VERSION 5.7 ;
  NOWIREEXTENSIONATPIN ON ;
  DIVIDERCHAR "/" ;
  BUSBITCHARS "[]" ;
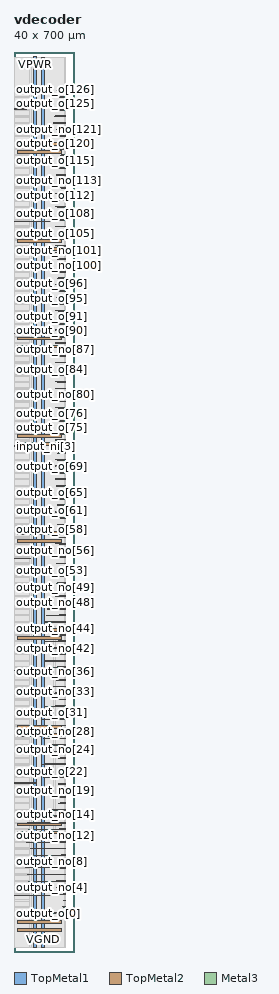
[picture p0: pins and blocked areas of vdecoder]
MACRO vdecoder
  CLASS BLOCK ;
  FOREIGN vdecoder ;
  ORIGIN 0.000 0.000 ;
  SIZE 40.000 BY 700.000 ;
  PIN VGND
    DIRECTION INOUT ;
    USE GROUND ;
    PORT
      LAYER TopMetal1 ;
        RECT 21.580 3.150 23.780 695.740 ;
    END
    PORT
      LAYER TopMetal2 ;
        RECT 2.660 22.480 37.180 24.680 ;
    END
    PORT
      LAYER TopMetal2 ;
        RECT 2.660 98.080 37.180 100.280 ;
    END
    PORT
      LAYER TopMetal2 ;
        RECT 2.660 173.680 37.180 175.880 ;
    END
    PORT
      LAYER TopMetal2 ;
        RECT 2.660 249.280 37.180 251.480 ;
    END
    PORT
      LAYER TopMetal2 ;
        RECT 2.660 324.880 37.180 327.080 ;
    END
    PORT
      LAYER TopMetal2 ;
        RECT 2.660 400.480 37.180 402.680 ;
    END
    PORT
      LAYER TopMetal2 ;
        RECT 2.660 476.080 37.180 478.280 ;
    END
    PORT
      LAYER TopMetal2 ;
        RECT 2.660 551.680 37.180 553.880 ;
    END
    PORT
      LAYER TopMetal2 ;
        RECT 2.660 627.280 37.180 629.480 ;
    END
  END VGND
  PIN VPWR
    DIRECTION INOUT ;
    USE POWER ;
    PORT
      LAYER TopMetal1 ;
        RECT 15.380 3.560 17.580 696.150 ;
    END
    PORT
      LAYER TopMetal2 ;
        RECT 2.660 16.280 37.180 18.480 ;
    END
    PORT
      LAYER TopMetal2 ;
        RECT 2.660 91.880 37.180 94.080 ;
    END
    PORT
      LAYER TopMetal2 ;
        RECT 2.660 167.480 37.180 169.680 ;
    END
    PORT
      LAYER TopMetal2 ;
        RECT 2.660 243.080 37.180 245.280 ;
    END
    PORT
      LAYER TopMetal2 ;
        RECT 2.660 318.680 37.180 320.880 ;
    END
    PORT
      LAYER TopMetal2 ;
        RECT 2.660 394.280 37.180 396.480 ;
    END
    PORT
      LAYER TopMetal2 ;
        RECT 2.660 469.880 37.180 472.080 ;
    END
    PORT
      LAYER TopMetal2 ;
        RECT 2.660 545.480 37.180 547.680 ;
    END
    PORT
      LAYER TopMetal2 ;
        RECT 2.660 621.080 37.180 623.280 ;
    END
  END VPWR
  PIN ena_i
    DIRECTION INPUT ;
    USE SIGNAL ;
    ANTENNAGATEAREA 7.350200 ;
    PORT
      LAYER Metal3 ;
        RECT 0.000 44.000 29.180 44.200 ;
    END
  END ena_i
  PIN input_ni[0]
    DIRECTION INPUT ;
    USE SIGNAL ;
    ANTENNAGATEAREA 1.992900 ;
    PORT
      LAYER Metal3 ;
        RECT 0.000 131.360 17.660 131.560 ;
    END
  END input_ni[0]
  PIN input_ni[1]
    DIRECTION INPUT ;
    USE SIGNAL ;
    ANTENNAGATEAREA 1.992900 ;
    PORT
      LAYER Metal3 ;
        RECT 0.000 218.720 18.620 218.920 ;
    END
  END input_ni[1]
  PIN input_ni[2]
    DIRECTION INPUT ;
    USE SIGNAL ;
    ANTENNAGATEAREA 3.706300 ;
    PORT
      LAYER Metal3 ;
        RECT 0.000 306.080 12.580 306.280 ;
    END
  END input_ni[2]
  PIN input_ni[3]
    DIRECTION INPUT ;
    USE SIGNAL ;
    ANTENNAGATEAREA 3.706300 ;
    PORT
      LAYER Metal3 ;
        RECT 0.000 393.440 1.060 393.640 ;
    END
  END input_ni[3]
  PIN input_ni[4]
    DIRECTION INPUT ;
    USE SIGNAL ;
    ANTENNAGATEAREA 2.008500 ;
    PORT
      LAYER Metal3 ;
        RECT 0.000 480.800 29.660 481.000 ;
    END
  END input_ni[4]
  PIN input_ni[5]
    DIRECTION INPUT ;
    USE SIGNAL ;
    ANTENNAGATEAREA 2.008500 ;
    PORT
      LAYER Metal3 ;
        RECT 0.000 568.160 28.700 568.360 ;
    END
  END input_ni[5]
  PIN input_ni[6]
    DIRECTION INPUT ;
    USE SIGNAL ;
    ANTENNAGATEAREA 2.984800 ;
    PORT
      LAYER Metal3 ;
        RECT 0.000 655.520 9.500 655.720 ;
    END
  END input_ni[6]
  PIN output_no[0]
    DIRECTION OUTPUT ;
    USE SIGNAL ;
    ANTENNADIFFAREA 0.677200 ;
    PORT
      LAYER Metal3 ;
        RECT 30.340 30.140 40.000 30.340 ;
    END
  END output_no[0]
  PIN output_no[100]
    DIRECTION OUTPUT ;
    USE SIGNAL ;
    ANTENNADIFFAREA 0.677200 ;
    PORT
      LAYER Metal3 ;
        RECT 36.100 534.140 40.000 534.340 ;
    END
  END output_no[100]
  PIN output_no[101]
    DIRECTION OUTPUT ;
    USE SIGNAL ;
    ANTENNADIFFAREA 0.677200 ;
    PORT
      LAYER Metal3 ;
        RECT 34.460 539.180 40.000 539.380 ;
    END
  END output_no[101]
  PIN output_no[102]
    DIRECTION OUTPUT ;
    USE SIGNAL ;
    ANTENNADIFFAREA 0.677200 ;
    PORT
      LAYER Metal3 ;
        RECT 32.260 544.220 40.000 544.420 ;
    END
  END output_no[102]
  PIN output_no[103]
    DIRECTION OUTPUT ;
    USE SIGNAL ;
    ANTENNADIFFAREA 0.677200 ;
    PORT
      LAYER Metal3 ;
        RECT 32.260 549.260 40.000 549.460 ;
    END
  END output_no[103]
  PIN output_no[104]
    DIRECTION OUTPUT ;
    USE SIGNAL ;
    ANTENNADIFFAREA 0.677200 ;
    PORT
      LAYER Metal3 ;
        RECT 36.100 554.300 40.000 554.500 ;
    END
  END output_no[104]
  PIN output_no[105]
    DIRECTION OUTPUT ;
    USE SIGNAL ;
    ANTENNADIFFAREA 0.677200 ;
    PORT
      LAYER Metal3 ;
        RECT 34.180 559.340 40.000 559.540 ;
    END
  END output_no[105]
  PIN output_no[106]
    DIRECTION OUTPUT ;
    USE SIGNAL ;
    ANTENNADIFFAREA 0.677200 ;
    PORT
      LAYER Metal3 ;
        RECT 32.260 564.380 40.000 564.580 ;
    END
  END output_no[106]
  PIN output_no[107]
    DIRECTION OUTPUT ;
    USE SIGNAL ;
    ANTENNADIFFAREA 0.677200 ;
    PORT
      LAYER Metal3 ;
        RECT 36.100 569.420 40.000 569.620 ;
    END
  END output_no[107]
  PIN output_no[108]
    DIRECTION OUTPUT ;
    USE SIGNAL ;
    ANTENNADIFFAREA 0.677200 ;
    PORT
      LAYER Metal3 ;
        RECT 34.180 574.460 40.000 574.660 ;
    END
  END output_no[108]
  PIN output_no[109]
    DIRECTION OUTPUT ;
    USE SIGNAL ;
    ANTENNADIFFAREA 0.677200 ;
    PORT
      LAYER Metal3 ;
        RECT 32.260 579.500 40.000 579.700 ;
    END
  END output_no[109]
  PIN output_no[10]
    DIRECTION OUTPUT ;
    USE SIGNAL ;
    ANTENNADIFFAREA 0.677200 ;
    PORT
      LAYER Metal3 ;
        RECT 36.580 80.540 40.000 80.740 ;
    END
  END output_no[10]
  PIN output_no[110]
    DIRECTION OUTPUT ;
    USE SIGNAL ;
    ANTENNADIFFAREA 0.677200 ;
    PORT
      LAYER Metal3 ;
        RECT 36.100 584.540 40.000 584.740 ;
    END
  END output_no[110]
  PIN output_no[111]
    DIRECTION OUTPUT ;
    USE SIGNAL ;
    ANTENNADIFFAREA 0.677200 ;
    PORT
      LAYER Metal3 ;
        RECT 32.260 589.580 40.000 589.780 ;
    END
  END output_no[111]
  PIN output_no[112]
    DIRECTION OUTPUT ;
    USE SIGNAL ;
    ANTENNADIFFAREA 0.677200 ;
    PORT
      LAYER Metal3 ;
        RECT 36.380 594.620 40.000 594.820 ;
    END
  END output_no[112]
  PIN output_no[113]
    DIRECTION OUTPUT ;
    USE SIGNAL ;
    ANTENNADIFFAREA 0.677200 ;
    PORT
      LAYER Metal3 ;
        RECT 38.780 599.660 40.000 599.860 ;
    END
  END output_no[113]
  PIN output_no[114]
    DIRECTION OUTPUT ;
    USE SIGNAL ;
    ANTENNADIFFAREA 0.677200 ;
    PORT
      LAYER Metal3 ;
        RECT 37.060 604.700 40.000 604.900 ;
    END
  END output_no[114]
  PIN output_no[115]
    DIRECTION OUTPUT ;
    USE SIGNAL ;
    ANTENNADIFFAREA 0.677200 ;
    PORT
      LAYER Metal3 ;
        RECT 30.340 609.740 40.000 609.940 ;
    END
  END output_no[115]
  PIN output_no[116]
    DIRECTION OUTPUT ;
    USE SIGNAL ;
    ANTENNADIFFAREA 0.677200 ;
    PORT
      LAYER Metal3 ;
        RECT 37.540 614.780 40.000 614.980 ;
    END
  END output_no[116]
  PIN output_no[117]
    DIRECTION OUTPUT ;
    USE SIGNAL ;
    ANTENNADIFFAREA 0.677200 ;
    PORT
      LAYER Metal3 ;
        RECT 37.060 619.820 40.000 620.020 ;
    END
  END output_no[117]
  PIN output_no[118]
    DIRECTION OUTPUT ;
    USE SIGNAL ;
    ANTENNADIFFAREA 0.677200 ;
    PORT
      LAYER Metal3 ;
        RECT 37.540 624.860 40.000 625.060 ;
    END
  END output_no[118]
  PIN output_no[119]
    DIRECTION OUTPUT ;
    USE SIGNAL ;
    ANTENNADIFFAREA 0.677200 ;
    PORT
      LAYER Metal3 ;
        RECT 35.420 629.900 40.000 630.100 ;
    END
  END output_no[119]
  PIN output_no[11]
    DIRECTION OUTPUT ;
    USE SIGNAL ;
    ANTENNADIFFAREA 0.677200 ;
    PORT
      LAYER Metal3 ;
        RECT 30.820 85.580 40.000 85.780 ;
    END
  END output_no[11]
  PIN output_no[120]
    DIRECTION OUTPUT ;
    USE SIGNAL ;
    ANTENNADIFFAREA 0.677200 ;
    PORT
      LAYER Metal3 ;
        RECT 31.780 634.940 40.000 635.140 ;
    END
  END output_no[120]
  PIN output_no[121]
    DIRECTION OUTPUT ;
    USE SIGNAL ;
    ANTENNADIFFAREA 0.677200 ;
    PORT
      LAYER Metal3 ;
        RECT 38.980 639.980 40.000 640.180 ;
    END
  END output_no[121]
  PIN output_no[122]
    DIRECTION OUTPUT ;
    USE SIGNAL ;
    ANTENNADIFFAREA 0.677200 ;
    PORT
      LAYER Metal3 ;
        RECT 34.180 645.020 40.000 645.220 ;
    END
  END output_no[122]
  PIN output_no[123]
    DIRECTION OUTPUT ;
    USE SIGNAL ;
    ANTENNADIFFAREA 0.677200 ;
    PORT
      LAYER Metal3 ;
        RECT 32.260 650.060 40.000 650.260 ;
    END
  END output_no[123]
  PIN output_no[124]
    DIRECTION OUTPUT ;
    USE SIGNAL ;
    ANTENNADIFFAREA 0.677200 ;
    PORT
      LAYER Metal3 ;
        RECT 30.820 655.100 40.000 655.300 ;
    END
  END output_no[124]
  PIN output_no[125]
    DIRECTION OUTPUT ;
    USE SIGNAL ;
    ANTENNADIFFAREA 0.677200 ;
    PORT
      LAYER Metal3 ;
        RECT 38.500 660.140 40.000 660.340 ;
    END
  END output_no[125]
  PIN output_no[126]
    DIRECTION OUTPUT ;
    USE SIGNAL ;
    ANTENNADIFFAREA 0.677200 ;
    PORT
      LAYER Metal3 ;
        RECT 31.780 665.180 40.000 665.380 ;
    END
  END output_no[126]
  PIN output_no[127]
    DIRECTION OUTPUT ;
    USE SIGNAL ;
    ANTENNADIFFAREA 0.677200 ;
    PORT
      LAYER Metal3 ;
        RECT 33.220 670.220 40.000 670.420 ;
    END
  END output_no[127]
  PIN output_no[12]
    DIRECTION OUTPUT ;
    USE SIGNAL ;
    ANTENNADIFFAREA 0.677200 ;
    PORT
      LAYER Metal3 ;
        RECT 38.780 90.620 40.000 90.820 ;
    END
  END output_no[12]
  PIN output_no[13]
    DIRECTION OUTPUT ;
    USE SIGNAL ;
    ANTENNADIFFAREA 0.677200 ;
    PORT
      LAYER Metal3 ;
        RECT 35.140 95.660 40.000 95.860 ;
    END
  END output_no[13]
  PIN output_no[14]
    DIRECTION OUTPUT ;
    USE SIGNAL ;
    ANTENNADIFFAREA 0.677200 ;
    PORT
      LAYER Metal3 ;
        RECT 37.060 100.700 40.000 100.900 ;
    END
  END output_no[14]
  PIN output_no[15]
    DIRECTION OUTPUT ;
    USE SIGNAL ;
    ANTENNADIFFAREA 0.677200 ;
    PORT
      LAYER Metal3 ;
        RECT 17.660 105.740 40.000 105.940 ;
    END
  END output_no[15]
  PIN output_no[16]
    DIRECTION OUTPUT ;
    USE SIGNAL ;
    ANTENNADIFFAREA 0.677200 ;
    PORT
      LAYER Metal3 ;
        RECT 32.060 110.780 40.000 110.980 ;
    END
  END output_no[16]
  PIN output_no[17]
    DIRECTION OUTPUT ;
    USE SIGNAL ;
    ANTENNADIFFAREA 0.677200 ;
    PORT
      LAYER Metal3 ;
        RECT 36.100 115.820 40.000 116.020 ;
    END
  END output_no[17]
  PIN output_no[18]
    DIRECTION OUTPUT ;
    USE SIGNAL ;
    ANTENNADIFFAREA 0.677200 ;
    PORT
      LAYER Metal3 ;
        RECT 36.100 120.860 40.000 121.060 ;
    END
  END output_no[18]
  PIN output_no[19]
    DIRECTION OUTPUT ;
    USE SIGNAL ;
    ANTENNADIFFAREA 0.677200 ;
    PORT
      LAYER Metal3 ;
        RECT 36.100 125.900 40.000 126.100 ;
    END
  END output_no[19]
  PIN output_no[1]
    DIRECTION OUTPUT ;
    USE SIGNAL ;
    ANTENNADIFFAREA 0.677200 ;
    PORT
      LAYER Metal3 ;
        RECT 38.020 35.180 40.000 35.380 ;
    END
  END output_no[1]
  PIN output_no[20]
    DIRECTION OUTPUT ;
    USE SIGNAL ;
    ANTENNADIFFAREA 0.677200 ;
    PORT
      LAYER Metal3 ;
        RECT 36.100 130.940 40.000 131.140 ;
    END
  END output_no[20]
  PIN output_no[21]
    DIRECTION OUTPUT ;
    USE SIGNAL ;
    ANTENNADIFFAREA 1.058000 ;
    PORT
      LAYER Metal3 ;
        RECT 34.660 135.980 40.000 136.180 ;
    END
  END output_no[21]
  PIN output_no[22]
    DIRECTION OUTPUT ;
    USE SIGNAL ;
    ANTENNADIFFAREA 1.058000 ;
    PORT
      LAYER Metal3 ;
        RECT 34.460 141.020 40.000 141.220 ;
    END
  END output_no[22]
  PIN output_no[23]
    DIRECTION OUTPUT ;
    USE SIGNAL ;
    ANTENNADIFFAREA 1.058000 ;
    PORT
      LAYER Metal3 ;
        RECT 24.860 146.060 40.000 146.260 ;
    END
  END output_no[23]
  PIN output_no[24]
    DIRECTION OUTPUT ;
    USE SIGNAL ;
    ANTENNADIFFAREA 0.677200 ;
    PORT
      LAYER Metal3 ;
        RECT 36.100 151.100 40.000 151.300 ;
    END
  END output_no[24]
  PIN output_no[25]
    DIRECTION OUTPUT ;
    USE SIGNAL ;
    ANTENNADIFFAREA 1.058000 ;
    PORT
      LAYER Metal3 ;
        RECT 33.980 156.140 40.000 156.340 ;
    END
  END output_no[25]
  PIN output_no[26]
    DIRECTION OUTPUT ;
    USE SIGNAL ;
    ANTENNADIFFAREA 1.058000 ;
    PORT
      LAYER Metal3 ;
        RECT 27.740 161.180 40.000 161.380 ;
    END
  END output_no[26]
  PIN output_no[27]
    DIRECTION OUTPUT ;
    USE SIGNAL ;
    ANTENNADIFFAREA 1.058000 ;
    PORT
      LAYER Metal3 ;
        RECT 28.420 166.220 40.000 166.420 ;
    END
  END output_no[27]
  PIN output_no[28]
    DIRECTION OUTPUT ;
    USE SIGNAL ;
    ANTENNADIFFAREA 0.677200 ;
    PORT
      LAYER Metal3 ;
        RECT 36.100 171.260 40.000 171.460 ;
    END
  END output_no[28]
  PIN output_no[29]
    DIRECTION OUTPUT ;
    USE SIGNAL ;
    ANTENNADIFFAREA 1.058000 ;
    PORT
      LAYER Metal3 ;
        RECT 34.660 176.300 40.000 176.500 ;
    END
  END output_no[29]
  PIN output_no[2]
    DIRECTION OUTPUT ;
    USE SIGNAL ;
    ANTENNADIFFAREA 0.677200 ;
    PORT
      LAYER Metal3 ;
        RECT 38.500 40.220 40.000 40.420 ;
    END
  END output_no[2]
  PIN output_no[30]
    DIRECTION OUTPUT ;
    USE SIGNAL ;
    ANTENNADIFFAREA 1.058000 ;
    PORT
      LAYER Metal3 ;
        RECT 34.660 181.340 40.000 181.540 ;
    END
  END output_no[30]
  PIN output_no[31]
    DIRECTION OUTPUT ;
    USE SIGNAL ;
    ANTENNADIFFAREA 0.677200 ;
    PORT
      LAYER Metal3 ;
        RECT 34.180 186.380 40.000 186.580 ;
    END
  END output_no[31]
  PIN output_no[32]
    DIRECTION OUTPUT ;
    USE SIGNAL ;
    ANTENNADIFFAREA 0.677200 ;
    PORT
      LAYER Metal3 ;
        RECT 32.260 191.420 40.000 191.620 ;
    END
  END output_no[32]
  PIN output_no[33]
    DIRECTION OUTPUT ;
    USE SIGNAL ;
    ANTENNADIFFAREA 0.677200 ;
    PORT
      LAYER Metal3 ;
        RECT 35.620 196.460 40.000 196.660 ;
    END
  END output_no[33]
  PIN output_no[34]
    DIRECTION OUTPUT ;
    USE SIGNAL ;
    ANTENNADIFFAREA 0.677200 ;
    PORT
      LAYER Metal3 ;
        RECT 32.260 201.500 40.000 201.700 ;
    END
  END output_no[34]
  PIN output_no[35]
    DIRECTION OUTPUT ;
    USE SIGNAL ;
    ANTENNADIFFAREA 0.677200 ;
    PORT
      LAYER Metal3 ;
        RECT 34.180 206.540 40.000 206.740 ;
    END
  END output_no[35]
  PIN output_no[36]
    DIRECTION OUTPUT ;
    USE SIGNAL ;
    ANTENNADIFFAREA 0.677200 ;
    PORT
      LAYER Metal3 ;
        RECT 34.660 211.580 40.000 211.780 ;
    END
  END output_no[36]
  PIN output_no[37]
    DIRECTION OUTPUT ;
    USE SIGNAL ;
    ANTENNADIFFAREA 1.058000 ;
    PORT
      LAYER Metal3 ;
        RECT 33.980 216.620 40.000 216.820 ;
    END
  END output_no[37]
  PIN output_no[38]
    DIRECTION OUTPUT ;
    USE SIGNAL ;
    ANTENNADIFFAREA 1.058000 ;
    PORT
      LAYER Metal3 ;
        RECT 33.980 221.660 40.000 221.860 ;
    END
  END output_no[38]
  PIN output_no[39]
    DIRECTION OUTPUT ;
    USE SIGNAL ;
    ANTENNADIFFAREA 1.058000 ;
    PORT
      LAYER Metal3 ;
        RECT 29.860 226.700 40.000 226.900 ;
    END
  END output_no[39]
  PIN output_no[3]
    DIRECTION OUTPUT ;
    USE SIGNAL ;
    ANTENNADIFFAREA 0.677200 ;
    PORT
      LAYER Metal3 ;
        RECT 38.780 45.260 40.000 45.460 ;
    END
  END output_no[3]
  PIN output_no[40]
    DIRECTION OUTPUT ;
    USE SIGNAL ;
    ANTENNADIFFAREA 0.677200 ;
    PORT
      LAYER Metal3 ;
        RECT 34.180 231.740 40.000 231.940 ;
    END
  END output_no[40]
  PIN output_no[41]
    DIRECTION OUTPUT ;
    USE SIGNAL ;
    ANTENNADIFFAREA 1.058000 ;
    PORT
      LAYER Metal3 ;
        RECT 33.700 236.780 40.000 236.980 ;
    END
  END output_no[41]
  PIN output_no[42]
    DIRECTION OUTPUT ;
    USE SIGNAL ;
    ANTENNADIFFAREA 1.058000 ;
    PORT
      LAYER Metal3 ;
        RECT 34.660 241.820 40.000 242.020 ;
    END
  END output_no[42]
  PIN output_no[43]
    DIRECTION OUTPUT ;
    USE SIGNAL ;
    ANTENNADIFFAREA 1.058000 ;
    PORT
      LAYER Metal3 ;
        RECT 28.700 246.860 40.000 247.060 ;
    END
  END output_no[43]
  PIN output_no[44]
    DIRECTION OUTPUT ;
    USE SIGNAL ;
    ANTENNADIFFAREA 0.677200 ;
    PORT
      LAYER Metal3 ;
        RECT 37.340 251.900 40.000 252.100 ;
    END
  END output_no[44]
  PIN output_no[45]
    DIRECTION OUTPUT ;
    USE SIGNAL ;
    ANTENNADIFFAREA 1.058000 ;
    PORT
      LAYER Metal3 ;
        RECT 34.180 256.940 40.000 257.140 ;
    END
  END output_no[45]
  PIN output_no[46]
    DIRECTION OUTPUT ;
    USE SIGNAL ;
    ANTENNADIFFAREA 1.058000 ;
    PORT
      LAYER Metal3 ;
        RECT 35.620 261.980 40.000 262.180 ;
    END
  END output_no[46]
  PIN output_no[47]
    DIRECTION OUTPUT ;
    USE SIGNAL ;
    ANTENNADIFFAREA 0.677200 ;
    PORT
      LAYER Metal3 ;
        RECT 32.260 267.020 40.000 267.220 ;
    END
  END output_no[47]
  PIN output_no[48]
    DIRECTION OUTPUT ;
    USE SIGNAL ;
    ANTENNADIFFAREA 0.677200 ;
    PORT
      LAYER Metal3 ;
        RECT 36.100 272.060 40.000 272.260 ;
    END
  END output_no[48]
  PIN output_no[49]
    DIRECTION OUTPUT ;
    USE SIGNAL ;
    ANTENNADIFFAREA 0.677200 ;
    PORT
      LAYER Metal3 ;
        RECT 34.180 277.100 40.000 277.300 ;
    END
  END output_no[49]
  PIN output_no[4]
    DIRECTION OUTPUT ;
    USE SIGNAL ;
    ANTENNADIFFAREA 0.677200 ;
    PORT
      LAYER Metal3 ;
        RECT 38.980 50.300 40.000 50.500 ;
    END
  END output_no[4]
  PIN output_no[50]
    DIRECTION OUTPUT ;
    USE SIGNAL ;
    ANTENNADIFFAREA 0.677200 ;
    PORT
      LAYER Metal3 ;
        RECT 34.180 282.140 40.000 282.340 ;
    END
  END output_no[50]
  PIN output_no[51]
    DIRECTION OUTPUT ;
    USE SIGNAL ;
    ANTENNADIFFAREA 0.677200 ;
    PORT
      LAYER Metal3 ;
        RECT 34.180 287.180 40.000 287.380 ;
    END
  END output_no[51]
  PIN output_no[52]
    DIRECTION OUTPUT ;
    USE SIGNAL ;
    ANTENNADIFFAREA 0.677200 ;
    PORT
      LAYER Metal3 ;
        RECT 34.180 292.220 40.000 292.420 ;
    END
  END output_no[52]
  PIN output_no[53]
    DIRECTION OUTPUT ;
    USE SIGNAL ;
    ANTENNADIFFAREA 0.677200 ;
    PORT
      LAYER Metal3 ;
        RECT 34.180 297.260 40.000 297.460 ;
    END
  END output_no[53]
  PIN output_no[54]
    DIRECTION OUTPUT ;
    USE SIGNAL ;
    ANTENNADIFFAREA 0.677200 ;
    PORT
      LAYER Metal3 ;
        RECT 34.180 302.300 40.000 302.500 ;
    END
  END output_no[54]
  PIN output_no[55]
    DIRECTION OUTPUT ;
    USE SIGNAL ;
    ANTENNADIFFAREA 0.677200 ;
    PORT
      LAYER Metal3 ;
        RECT 34.180 307.340 40.000 307.540 ;
    END
  END output_no[55]
  PIN output_no[56]
    DIRECTION OUTPUT ;
    USE SIGNAL ;
    ANTENNADIFFAREA 0.677200 ;
    PORT
      LAYER Metal3 ;
        RECT 36.380 312.380 40.000 312.580 ;
    END
  END output_no[56]
  PIN output_no[57]
    DIRECTION OUTPUT ;
    USE SIGNAL ;
    ANTENNADIFFAREA 0.677200 ;
    PORT
      LAYER Metal3 ;
        RECT 32.260 317.420 40.000 317.620 ;
    END
  END output_no[57]
  PIN output_no[58]
    DIRECTION OUTPUT ;
    USE SIGNAL ;
    ANTENNADIFFAREA 0.677200 ;
    PORT
      LAYER Metal3 ;
        RECT 34.660 322.460 40.000 322.660 ;
    END
  END output_no[58]
  PIN output_no[59]
    DIRECTION OUTPUT ;
    USE SIGNAL ;
    ANTENNADIFFAREA 0.677200 ;
    PORT
      LAYER Metal3 ;
        RECT 35.620 327.500 40.000 327.700 ;
    END
  END output_no[59]
  PIN output_no[5]
    DIRECTION OUTPUT ;
    USE SIGNAL ;
    ANTENNADIFFAREA 0.677200 ;
    PORT
      LAYER Metal3 ;
        RECT 32.740 55.340 40.000 55.540 ;
    END
  END output_no[5]
  PIN output_no[60]
    DIRECTION OUTPUT ;
    USE SIGNAL ;
    ANTENNADIFFAREA 0.677200 ;
    PORT
      LAYER Metal3 ;
        RECT 34.180 332.540 40.000 332.740 ;
    END
  END output_no[60]
  PIN output_no[61]
    DIRECTION OUTPUT ;
    USE SIGNAL ;
    ANTENNADIFFAREA 0.677200 ;
    PORT
      LAYER Metal3 ;
        RECT 34.180 337.580 40.000 337.780 ;
    END
  END output_no[61]
  PIN output_no[62]
    DIRECTION OUTPUT ;
    USE SIGNAL ;
    ANTENNADIFFAREA 0.677200 ;
    PORT
      LAYER Metal3 ;
        RECT 34.180 342.620 40.000 342.820 ;
    END
  END output_no[62]
  PIN output_no[63]
    DIRECTION OUTPUT ;
    USE SIGNAL ;
    ANTENNADIFFAREA 0.677200 ;
    PORT
      LAYER Metal3 ;
        RECT 34.180 347.660 40.000 347.860 ;
    END
  END output_no[63]
  PIN output_no[64]
    DIRECTION OUTPUT ;
    USE SIGNAL ;
    ANTENNADIFFAREA 0.677200 ;
    PORT
      LAYER Metal3 ;
        RECT 34.180 352.700 40.000 352.900 ;
    END
  END output_no[64]
  PIN output_no[65]
    DIRECTION OUTPUT ;
    USE SIGNAL ;
    ANTENNADIFFAREA 0.677200 ;
    PORT
      LAYER Metal3 ;
        RECT 33.980 357.740 40.000 357.940 ;
    END
  END output_no[65]
  PIN output_no[66]
    DIRECTION OUTPUT ;
    USE SIGNAL ;
    ANTENNADIFFAREA 0.677200 ;
    PORT
      LAYER Metal3 ;
        RECT 34.180 362.780 40.000 362.980 ;
    END
  END output_no[66]
  PIN output_no[67]
    DIRECTION OUTPUT ;
    USE SIGNAL ;
    ANTENNADIFFAREA 0.677200 ;
    PORT
      LAYER Metal3 ;
        RECT 32.260 367.820 40.000 368.020 ;
    END
  END output_no[67]
  PIN output_no[68]
    DIRECTION OUTPUT ;
    USE SIGNAL ;
    ANTENNADIFFAREA 0.677200 ;
    PORT
      LAYER Metal3 ;
        RECT 32.260 372.860 40.000 373.060 ;
    END
  END output_no[68]
  PIN output_no[69]
    DIRECTION OUTPUT ;
    USE SIGNAL ;
    ANTENNADIFFAREA 0.677200 ;
    PORT
      LAYER Metal3 ;
        RECT 32.260 377.900 40.000 378.100 ;
    END
  END output_no[69]
  PIN output_no[6]
    DIRECTION OUTPUT ;
    USE SIGNAL ;
    ANTENNADIFFAREA 0.677200 ;
    PORT
      LAYER Metal3 ;
        RECT 18.820 60.380 40.000 60.580 ;
    END
  END output_no[6]
  PIN output_no[70]
    DIRECTION OUTPUT ;
    USE SIGNAL ;
    ANTENNADIFFAREA 0.677200 ;
    PORT
      LAYER Metal3 ;
        RECT 32.260 382.940 40.000 383.140 ;
    END
  END output_no[70]
  PIN output_no[71]
    DIRECTION OUTPUT ;
    USE SIGNAL ;
    ANTENNADIFFAREA 0.677200 ;
    PORT
      LAYER Metal3 ;
        RECT 34.460 387.980 40.000 388.180 ;
    END
  END output_no[71]
  PIN output_no[72]
    DIRECTION OUTPUT ;
    USE SIGNAL ;
    ANTENNADIFFAREA 0.677200 ;
    PORT
      LAYER Metal3 ;
        RECT 32.260 393.020 40.000 393.220 ;
    END
  END output_no[72]
  PIN output_no[73]
    DIRECTION OUTPUT ;
    USE SIGNAL ;
    ANTENNADIFFAREA 0.677200 ;
    PORT
      LAYER Metal3 ;
        RECT 32.260 398.060 40.000 398.260 ;
    END
  END output_no[73]
  PIN output_no[74]
    DIRECTION OUTPUT ;
    USE SIGNAL ;
    ANTENNADIFFAREA 0.677200 ;
    PORT
      LAYER Metal3 ;
        RECT 32.260 403.100 40.000 403.300 ;
    END
  END output_no[74]
  PIN output_no[75]
    DIRECTION OUTPUT ;
    USE SIGNAL ;
    ANTENNADIFFAREA 0.677200 ;
    PORT
      LAYER Metal3 ;
        RECT 34.180 408.140 40.000 408.340 ;
    END
  END output_no[75]
  PIN output_no[76]
    DIRECTION OUTPUT ;
    USE SIGNAL ;
    ANTENNADIFFAREA 0.677200 ;
    PORT
      LAYER Metal3 ;
        RECT 32.260 413.180 40.000 413.380 ;
    END
  END output_no[76]
  PIN output_no[77]
    DIRECTION OUTPUT ;
    USE SIGNAL ;
    ANTENNADIFFAREA 0.677200 ;
    PORT
      LAYER Metal3 ;
        RECT 34.460 418.220 40.000 418.420 ;
    END
  END output_no[77]
  PIN output_no[78]
    DIRECTION OUTPUT ;
    USE SIGNAL ;
    ANTENNADIFFAREA 0.677200 ;
    PORT
      LAYER Metal3 ;
        RECT 32.260 423.260 40.000 423.460 ;
    END
  END output_no[78]
  PIN output_no[79]
    DIRECTION OUTPUT ;
    USE SIGNAL ;
    ANTENNADIFFAREA 0.677200 ;
    PORT
      LAYER Metal3 ;
        RECT 32.260 428.300 40.000 428.500 ;
    END
  END output_no[79]
  PIN output_no[7]
    DIRECTION OUTPUT ;
    USE SIGNAL ;
    ANTENNADIFFAREA 0.677200 ;
    PORT
      LAYER Metal3 ;
        RECT 8.740 65.420 40.000 65.620 ;
    END
  END output_no[7]
  PIN output_no[80]
    DIRECTION OUTPUT ;
    USE SIGNAL ;
    ANTENNADIFFAREA 0.677200 ;
    PORT
      LAYER Metal3 ;
        RECT 36.100 433.340 40.000 433.540 ;
    END
  END output_no[80]
  PIN output_no[81]
    DIRECTION OUTPUT ;
    USE SIGNAL ;
    ANTENNADIFFAREA 0.677200 ;
    PORT
      LAYER Metal3 ;
        RECT 32.260 438.380 40.000 438.580 ;
    END
  END output_no[81]
  PIN output_no[82]
    DIRECTION OUTPUT ;
    USE SIGNAL ;
    ANTENNADIFFAREA 0.677200 ;
    PORT
      LAYER Metal3 ;
        RECT 32.260 443.420 40.000 443.620 ;
    END
  END output_no[82]
  PIN output_no[83]
    DIRECTION OUTPUT ;
    USE SIGNAL ;
    ANTENNADIFFAREA 0.677200 ;
    PORT
      LAYER Metal3 ;
        RECT 34.460 448.460 40.000 448.660 ;
    END
  END output_no[83]
  PIN output_no[84]
    DIRECTION OUTPUT ;
    USE SIGNAL ;
    ANTENNADIFFAREA 0.677200 ;
    PORT
      LAYER Metal3 ;
        RECT 33.980 453.500 40.000 453.700 ;
    END
  END output_no[84]
  PIN output_no[85]
    DIRECTION OUTPUT ;
    USE SIGNAL ;
    ANTENNADIFFAREA 0.677200 ;
    PORT
      LAYER Metal3 ;
        RECT 32.260 458.540 40.000 458.740 ;
    END
  END output_no[85]
  PIN output_no[86]
    DIRECTION OUTPUT ;
    USE SIGNAL ;
    ANTENNADIFFAREA 0.677200 ;
    PORT
      LAYER Metal3 ;
        RECT 34.460 463.580 40.000 463.780 ;
    END
  END output_no[86]
  PIN output_no[87]
    DIRECTION OUTPUT ;
    USE SIGNAL ;
    ANTENNADIFFAREA 0.677200 ;
    PORT
      LAYER Metal3 ;
        RECT 38.780 468.620 40.000 468.820 ;
    END
  END output_no[87]
  PIN output_no[88]
    DIRECTION OUTPUT ;
    USE SIGNAL ;
    ANTENNADIFFAREA 0.677200 ;
    PORT
      LAYER Metal3 ;
        RECT 32.260 473.660 40.000 473.860 ;
    END
  END output_no[88]
  PIN output_no[89]
    DIRECTION OUTPUT ;
    USE SIGNAL ;
    ANTENNADIFFAREA 0.677200 ;
    PORT
      LAYER Metal3 ;
        RECT 34.460 478.700 40.000 478.900 ;
    END
  END output_no[89]
  PIN output_no[8]
    DIRECTION OUTPUT ;
    USE SIGNAL ;
    ANTENNADIFFAREA 0.677200 ;
    PORT
      LAYER Metal3 ;
        RECT 38.020 70.460 40.000 70.660 ;
    END
  END output_no[8]
  PIN output_no[90]
    DIRECTION OUTPUT ;
    USE SIGNAL ;
    ANTENNADIFFAREA 0.677200 ;
    PORT
      LAYER Metal3 ;
        RECT 32.260 483.740 40.000 483.940 ;
    END
  END output_no[90]
  PIN output_no[91]
    DIRECTION OUTPUT ;
    USE SIGNAL ;
    ANTENNADIFFAREA 0.677200 ;
    PORT
      LAYER Metal3 ;
        RECT 32.260 488.780 40.000 488.980 ;
    END
  END output_no[91]
  PIN output_no[92]
    DIRECTION OUTPUT ;
    USE SIGNAL ;
    ANTENNADIFFAREA 0.677200 ;
    PORT
      LAYER Metal3 ;
        RECT 34.460 493.820 40.000 494.020 ;
    END
  END output_no[92]
  PIN output_no[93]
    DIRECTION OUTPUT ;
    USE SIGNAL ;
    ANTENNADIFFAREA 0.677200 ;
    PORT
      LAYER Metal3 ;
        RECT 32.260 498.860 40.000 499.060 ;
    END
  END output_no[93]
  PIN output_no[94]
    DIRECTION OUTPUT ;
    USE SIGNAL ;
    ANTENNADIFFAREA 0.677200 ;
    PORT
      LAYER Metal3 ;
        RECT 32.260 503.900 40.000 504.100 ;
    END
  END output_no[94]
  PIN output_no[95]
    DIRECTION OUTPUT ;
    USE SIGNAL ;
    ANTENNADIFFAREA 0.677200 ;
    PORT
      LAYER Metal3 ;
        RECT 33.220 508.940 40.000 509.140 ;
    END
  END output_no[95]
  PIN output_no[96]
    DIRECTION OUTPUT ;
    USE SIGNAL ;
    ANTENNADIFFAREA 0.677200 ;
    PORT
      LAYER Metal3 ;
        RECT 34.180 513.980 40.000 514.180 ;
    END
  END output_no[96]
  PIN output_no[97]
    DIRECTION OUTPUT ;
    USE SIGNAL ;
    ANTENNADIFFAREA 0.677200 ;
    PORT
      LAYER Metal3 ;
        RECT 32.260 519.020 40.000 519.220 ;
    END
  END output_no[97]
  PIN output_no[98]
    DIRECTION OUTPUT ;
    USE SIGNAL ;
    ANTENNADIFFAREA 0.677200 ;
    PORT
      LAYER Metal3 ;
        RECT 34.460 524.060 40.000 524.260 ;
    END
  END output_no[98]
  PIN output_no[99]
    DIRECTION OUTPUT ;
    USE SIGNAL ;
    ANTENNADIFFAREA 0.677200 ;
    PORT
      LAYER Metal3 ;
        RECT 32.260 529.100 40.000 529.300 ;
    END
  END output_no[99]
  PIN output_no[9]
    DIRECTION OUTPUT ;
    USE SIGNAL ;
    ANTENNADIFFAREA 0.677200 ;
    PORT
      LAYER Metal3 ;
        RECT 36.860 75.500 40.000 75.700 ;
    END
  END output_no[9]
  PIN output_o[0]
    DIRECTION OUTPUT ;
    USE SIGNAL ;
    ANTENNADIFFAREA 0.662000 ;
    PORT
      LAYER Metal3 ;
        RECT 38.980 29.720 40.000 29.920 ;
    END
  END output_o[0]
  PIN output_o[100]
    DIRECTION OUTPUT ;
    USE SIGNAL ;
    ANTENNADIFFAREA 0.662000 ;
    PORT
      LAYER Metal3 ;
        RECT 34.180 533.720 40.000 533.920 ;
    END
  END output_o[100]
  PIN output_o[101]
    DIRECTION OUTPUT ;
    USE SIGNAL ;
    ANTENNADIFFAREA 0.662000 ;
    PORT
      LAYER Metal3 ;
        RECT 33.980 538.760 40.000 538.960 ;
    END
  END output_o[101]
  PIN output_o[102]
    DIRECTION OUTPUT ;
    USE SIGNAL ;
    ANTENNADIFFAREA 0.662000 ;
    PORT
      LAYER Metal3 ;
        RECT 34.660 543.800 40.000 544.000 ;
    END
  END output_o[102]
  PIN output_o[103]
    DIRECTION OUTPUT ;
    USE SIGNAL ;
    ANTENNADIFFAREA 0.662000 ;
    PORT
      LAYER Metal3 ;
        RECT 34.180 548.840 40.000 549.040 ;
    END
  END output_o[103]
  PIN output_o[104]
    DIRECTION OUTPUT ;
    USE SIGNAL ;
    ANTENNADIFFAREA 0.662000 ;
    PORT
      LAYER Metal3 ;
        RECT 32.060 553.880 40.000 554.080 ;
    END
  END output_o[104]
  PIN output_o[105]
    DIRECTION OUTPUT ;
    USE SIGNAL ;
    ANTENNADIFFAREA 0.662000 ;
    PORT
      LAYER Metal3 ;
        RECT 36.580 558.920 40.000 559.120 ;
    END
  END output_o[105]
  PIN output_o[106]
    DIRECTION OUTPUT ;
    USE SIGNAL ;
    ANTENNADIFFAREA 0.662000 ;
    PORT
      LAYER Metal3 ;
        RECT 34.180 563.960 40.000 564.160 ;
    END
  END output_o[106]
  PIN output_o[107]
    DIRECTION OUTPUT ;
    USE SIGNAL ;
    ANTENNADIFFAREA 0.662000 ;
    PORT
      LAYER Metal3 ;
        RECT 32.060 569.000 40.000 569.200 ;
    END
  END output_o[107]
  PIN output_o[108]
    DIRECTION OUTPUT ;
    USE SIGNAL ;
    ANTENNADIFFAREA 0.662000 ;
    PORT
      LAYER Metal3 ;
        RECT 36.580 574.040 40.000 574.240 ;
    END
  END output_o[108]
  PIN output_o[109]
    DIRECTION OUTPUT ;
    USE SIGNAL ;
    ANTENNADIFFAREA 0.662000 ;
    PORT
      LAYER Metal3 ;
        RECT 34.180 579.080 40.000 579.280 ;
    END
  END output_o[109]
  PIN output_o[10]
    DIRECTION OUTPUT ;
    USE SIGNAL ;
    ANTENNADIFFAREA 0.662000 ;
    PORT
      LAYER Metal3 ;
        RECT 12.580 80.120 40.000 80.320 ;
    END
  END output_o[10]
  PIN output_o[110]
    DIRECTION OUTPUT ;
    USE SIGNAL ;
    ANTENNADIFFAREA 0.662000 ;
    PORT
      LAYER Metal3 ;
        RECT 33.220 584.120 40.000 584.320 ;
    END
  END output_o[110]
  PIN output_o[111]
    DIRECTION OUTPUT ;
    USE SIGNAL ;
    ANTENNADIFFAREA 0.662000 ;
    PORT
      LAYER Metal3 ;
        RECT 34.660 589.160 40.000 589.360 ;
    END
  END output_o[111]
  PIN output_o[112]
    DIRECTION OUTPUT ;
    USE SIGNAL ;
    ANTENNADIFFAREA 0.662000 ;
    PORT
      LAYER Metal3 ;
        RECT 36.860 594.200 40.000 594.400 ;
    END
  END output_o[112]
  PIN output_o[113]
    DIRECTION OUTPUT ;
    USE SIGNAL ;
    ANTENNADIFFAREA 0.662000 ;
    PORT
      LAYER Metal3 ;
        RECT 33.980 599.240 40.000 599.440 ;
    END
  END output_o[113]
  PIN output_o[114]
    DIRECTION OUTPUT ;
    USE SIGNAL ;
    ANTENNADIFFAREA 0.662000 ;
    PORT
      LAYER Metal3 ;
        RECT 32.740 604.280 40.000 604.480 ;
    END
  END output_o[114]
  PIN output_o[115]
    DIRECTION OUTPUT ;
    USE SIGNAL ;
    ANTENNADIFFAREA 0.662000 ;
    PORT
      LAYER Metal3 ;
        RECT 38.020 609.320 40.000 609.520 ;
    END
  END output_o[115]
  PIN output_o[116]
    DIRECTION OUTPUT ;
    USE SIGNAL ;
    ANTENNADIFFAREA 0.662000 ;
    PORT
      LAYER Metal3 ;
        RECT 34.660 614.360 40.000 614.560 ;
    END
  END output_o[116]
  PIN output_o[117]
    DIRECTION OUTPUT ;
    USE SIGNAL ;
    ANTENNADIFFAREA 0.662000 ;
    PORT
      LAYER Metal3 ;
        RECT 36.100 619.400 40.000 619.600 ;
    END
  END output_o[117]
  PIN output_o[118]
    DIRECTION OUTPUT ;
    USE SIGNAL ;
    ANTENNADIFFAREA 0.662000 ;
    PORT
      LAYER Metal3 ;
        RECT 29.860 624.440 40.000 624.640 ;
    END
  END output_o[118]
  PIN output_o[119]
    DIRECTION OUTPUT ;
    USE SIGNAL ;
    ANTENNADIFFAREA 0.662000 ;
    PORT
      LAYER Metal3 ;
        RECT 36.100 629.480 40.000 629.680 ;
    END
  END output_o[119]
  PIN output_o[11]
    DIRECTION OUTPUT ;
    USE SIGNAL ;
    ANTENNADIFFAREA 0.662000 ;
    PORT
      LAYER Metal3 ;
        RECT 9.700 85.160 40.000 85.360 ;
    END
  END output_o[11]
  PIN output_o[120]
    DIRECTION OUTPUT ;
    USE SIGNAL ;
    ANTENNADIFFAREA 0.662000 ;
    PORT
      LAYER Metal3 ;
        RECT 34.660 634.520 40.000 634.720 ;
    END
  END output_o[120]
  PIN output_o[121]
    DIRECTION OUTPUT ;
    USE SIGNAL ;
    ANTENNADIFFAREA 0.662000 ;
    PORT
      LAYER Metal3 ;
        RECT 32.740 639.560 40.000 639.760 ;
    END
  END output_o[121]
  PIN output_o[122]
    DIRECTION OUTPUT ;
    USE SIGNAL ;
    ANTENNADIFFAREA 0.662000 ;
    PORT
      LAYER Metal3 ;
        RECT 30.340 644.600 40.000 644.800 ;
    END
  END output_o[122]
  PIN output_o[123]
    DIRECTION OUTPUT ;
    USE SIGNAL ;
    ANTENNADIFFAREA 0.662000 ;
    PORT
      LAYER Metal3 ;
        RECT 31.300 649.640 40.000 649.840 ;
    END
  END output_o[123]
  PIN output_o[124]
    DIRECTION OUTPUT ;
    USE SIGNAL ;
    ANTENNADIFFAREA 0.662000 ;
    PORT
      LAYER Metal3 ;
        RECT 33.700 654.680 40.000 654.880 ;
    END
  END output_o[124]
  PIN output_o[125]
    DIRECTION OUTPUT ;
    USE SIGNAL ;
    ANTENNADIFFAREA 0.662000 ;
    PORT
      LAYER Metal3 ;
        RECT 38.980 659.720 40.000 659.920 ;
    END
  END output_o[125]
  PIN output_o[126]
    DIRECTION OUTPUT ;
    USE SIGNAL ;
    ANTENNADIFFAREA 0.662000 ;
    PORT
      LAYER Metal3 ;
        RECT 35.140 664.760 40.000 664.960 ;
    END
  END output_o[126]
  PIN output_o[127]
    DIRECTION OUTPUT ;
    USE SIGNAL ;
    ANTENNADIFFAREA 0.662000 ;
    PORT
      LAYER Metal3 ;
        RECT 32.740 669.800 40.000 670.000 ;
    END
  END output_o[127]
  PIN output_o[12]
    DIRECTION OUTPUT ;
    USE SIGNAL ;
    ANTENNADIFFAREA 0.662000 ;
    PORT
      LAYER Metal3 ;
        RECT 34.180 90.200 40.000 90.400 ;
    END
  END output_o[12]
  PIN output_o[13]
    DIRECTION OUTPUT ;
    USE SIGNAL ;
    ANTENNADIFFAREA 0.662000 ;
    PORT
      LAYER Metal3 ;
        RECT 11.140 95.240 40.000 95.440 ;
    END
  END output_o[13]
  PIN output_o[14]
    DIRECTION OUTPUT ;
    USE SIGNAL ;
    ANTENNADIFFAREA 0.662000 ;
    PORT
      LAYER Metal3 ;
        RECT 10.660 100.280 40.000 100.480 ;
    END
  END output_o[14]
  PIN output_o[15]
    DIRECTION OUTPUT ;
    USE SIGNAL ;
    ANTENNADIFFAREA 0.662000 ;
    PORT
      LAYER Metal3 ;
        RECT 12.100 105.320 40.000 105.520 ;
    END
  END output_o[15]
  PIN output_o[16]
    DIRECTION OUTPUT ;
    USE SIGNAL ;
    ANTENNADIFFAREA 0.662000 ;
    PORT
      LAYER Metal3 ;
        RECT 27.460 110.360 40.000 110.560 ;
    END
  END output_o[16]
  PIN output_o[17]
    DIRECTION OUTPUT ;
    USE SIGNAL ;
    ANTENNADIFFAREA 0.632400 ;
    PORT
      LAYER Metal3 ;
        RECT 34.660 115.400 40.000 115.600 ;
    END
  END output_o[17]
  PIN output_o[18]
    DIRECTION OUTPUT ;
    USE SIGNAL ;
    ANTENNADIFFAREA 0.632400 ;
    PORT
      LAYER Metal3 ;
        RECT 34.660 120.440 40.000 120.640 ;
    END
  END output_o[18]
  PIN output_o[19]
    DIRECTION OUTPUT ;
    USE SIGNAL ;
    ANTENNADIFFAREA 0.632400 ;
    PORT
      LAYER Metal3 ;
        RECT 34.660 125.480 40.000 125.680 ;
    END
  END output_o[19]
  PIN output_o[1]
    DIRECTION OUTPUT ;
    USE SIGNAL ;
    ANTENNADIFFAREA 0.662000 ;
    PORT
      LAYER Metal3 ;
        RECT 38.780 34.760 40.000 34.960 ;
    END
  END output_o[1]
  PIN output_o[20]
    DIRECTION OUTPUT ;
    USE SIGNAL ;
    ANTENNADIFFAREA 0.632400 ;
    PORT
      LAYER Metal3 ;
        RECT 34.460 130.520 40.000 130.720 ;
    END
  END output_o[20]
  PIN output_o[21]
    DIRECTION OUTPUT ;
    USE SIGNAL ;
    ANTENNADIFFAREA 0.981400 ;
    PORT
      LAYER Metal3 ;
        RECT 22.660 135.560 40.000 135.760 ;
    END
  END output_o[21]
  PIN output_o[22]
    DIRECTION OUTPUT ;
    USE SIGNAL ;
    ANTENNADIFFAREA 0.981400 ;
    PORT
      LAYER Metal3 ;
        RECT 38.780 140.600 40.000 140.800 ;
    END
  END output_o[22]
  PIN output_o[23]
    DIRECTION OUTPUT ;
    USE SIGNAL ;
    ANTENNADIFFAREA 0.981400 ;
    PORT
      LAYER Metal3 ;
        RECT 21.700 145.640 40.000 145.840 ;
    END
  END output_o[23]
  PIN output_o[24]
    DIRECTION OUTPUT ;
    USE SIGNAL ;
    ANTENNADIFFAREA 0.632400 ;
    PORT
      LAYER Metal3 ;
        RECT 34.660 150.680 40.000 150.880 ;
    END
  END output_o[24]
  PIN output_o[25]
    DIRECTION OUTPUT ;
    USE SIGNAL ;
    ANTENNADIFFAREA 0.981400 ;
    PORT
      LAYER Metal3 ;
        RECT 21.700 155.720 40.000 155.920 ;
    END
  END output_o[25]
  PIN output_o[26]
    DIRECTION OUTPUT ;
    USE SIGNAL ;
    ANTENNADIFFAREA 0.981400 ;
    PORT
      LAYER Metal3 ;
        RECT 21.700 160.760 40.000 160.960 ;
    END
  END output_o[26]
  PIN output_o[27]
    DIRECTION OUTPUT ;
    USE SIGNAL ;
    ANTENNADIFFAREA 0.981400 ;
    PORT
      LAYER Metal3 ;
        RECT 22.660 165.800 40.000 166.000 ;
    END
  END output_o[27]
  PIN output_o[28]
    DIRECTION OUTPUT ;
    USE SIGNAL ;
    ANTENNADIFFAREA 0.632400 ;
    PORT
      LAYER Metal3 ;
        RECT 34.660 170.840 40.000 171.040 ;
    END
  END output_o[28]
  PIN output_o[29]
    DIRECTION OUTPUT ;
    USE SIGNAL ;
    ANTENNADIFFAREA 0.999200 ;
    PORT
      LAYER Metal3 ;
        RECT 21.220 175.880 40.000 176.080 ;
    END
  END output_o[29]
  PIN output_o[2]
    DIRECTION OUTPUT ;
    USE SIGNAL ;
    ANTENNADIFFAREA 0.662000 ;
    PORT
      LAYER Metal3 ;
        RECT 38.500 39.800 40.000 40.000 ;
    END
  END output_o[2]
  PIN output_o[30]
    DIRECTION OUTPUT ;
    USE SIGNAL ;
    ANTENNADIFFAREA 0.999200 ;
    PORT
      LAYER Metal3 ;
        RECT 21.700 180.920 40.000 181.120 ;
    END
  END output_o[30]
  PIN output_o[31]
    DIRECTION OUTPUT ;
    USE SIGNAL ;
    ANTENNADIFFAREA 0.662000 ;
    PORT
      LAYER Metal3 ;
        RECT 35.900 185.960 40.000 186.160 ;
    END
  END output_o[31]
  PIN output_o[32]
    DIRECTION OUTPUT ;
    USE SIGNAL ;
    ANTENNADIFFAREA 0.662000 ;
    PORT
      LAYER Metal3 ;
        RECT 24.380 191.000 40.000 191.200 ;
    END
  END output_o[32]
  PIN output_o[33]
    DIRECTION OUTPUT ;
    USE SIGNAL ;
    ANTENNADIFFAREA 0.632400 ;
    PORT
      LAYER Metal3 ;
        RECT 34.180 196.040 40.000 196.240 ;
    END
  END output_o[33]
  PIN output_o[34]
    DIRECTION OUTPUT ;
    USE SIGNAL ;
    ANTENNADIFFAREA 0.632400 ;
    PORT
      LAYER Metal3 ;
        RECT 28.900 201.080 40.000 201.280 ;
    END
  END output_o[34]
  PIN output_o[35]
    DIRECTION OUTPUT ;
    USE SIGNAL ;
    ANTENNADIFFAREA 0.632400 ;
    PORT
      LAYER Metal3 ;
        RECT 30.620 206.120 40.000 206.320 ;
    END
  END output_o[35]
  PIN output_o[36]
    DIRECTION OUTPUT ;
    USE SIGNAL ;
    ANTENNADIFFAREA 0.632400 ;
    PORT
      LAYER Metal3 ;
        RECT 33.220 211.160 40.000 211.360 ;
    END
  END output_o[36]
  PIN output_o[37]
    DIRECTION OUTPUT ;
    USE SIGNAL ;
    ANTENNADIFFAREA 0.981400 ;
    PORT
      LAYER Metal3 ;
        RECT 34.460 216.200 40.000 216.400 ;
    END
  END output_o[37]
  PIN output_o[38]
    DIRECTION OUTPUT ;
    USE SIGNAL ;
    ANTENNADIFFAREA 0.981400 ;
    PORT
      LAYER Metal3 ;
        RECT 23.140 221.240 40.000 221.440 ;
    END
  END output_o[38]
  PIN output_o[39]
    DIRECTION OUTPUT ;
    USE SIGNAL ;
    ANTENNADIFFAREA 0.981400 ;
    PORT
      LAYER Metal3 ;
        RECT 23.620 226.280 40.000 226.480 ;
    END
  END output_o[39]
  PIN output_o[3]
    DIRECTION OUTPUT ;
    USE SIGNAL ;
    ANTENNADIFFAREA 0.662000 ;
    PORT
      LAYER Metal3 ;
        RECT 34.660 44.840 40.000 45.040 ;
    END
  END output_o[3]
  PIN output_o[40]
    DIRECTION OUTPUT ;
    USE SIGNAL ;
    ANTENNADIFFAREA 0.632400 ;
    PORT
      LAYER Metal3 ;
        RECT 34.660 231.320 40.000 231.520 ;
    END
  END output_o[40]
  PIN output_o[41]
    DIRECTION OUTPUT ;
    USE SIGNAL ;
    ANTENNADIFFAREA 0.981400 ;
    PORT
      LAYER Metal3 ;
        RECT 24.100 236.360 40.000 236.560 ;
    END
  END output_o[41]
  PIN output_o[42]
    DIRECTION OUTPUT ;
    USE SIGNAL ;
    ANTENNADIFFAREA 0.981400 ;
    PORT
      LAYER Metal3 ;
        RECT 24.580 241.400 40.000 241.600 ;
    END
  END output_o[42]
  PIN output_o[43]
    DIRECTION OUTPUT ;
    USE SIGNAL ;
    ANTENNADIFFAREA 0.981400 ;
    PORT
      LAYER Metal3 ;
        RECT 29.180 246.440 40.000 246.640 ;
    END
  END output_o[43]
  PIN output_o[44]
    DIRECTION OUTPUT ;
    USE SIGNAL ;
    ANTENNADIFFAREA 0.632400 ;
    PORT
      LAYER Metal3 ;
        RECT 34.660 251.480 40.000 251.680 ;
    END
  END output_o[44]
  PIN output_o[45]
    DIRECTION OUTPUT ;
    USE SIGNAL ;
    ANTENNADIFFAREA 0.999200 ;
    PORT
      LAYER Metal3 ;
        RECT 24.580 256.520 40.000 256.720 ;
    END
  END output_o[45]
  PIN output_o[46]
    DIRECTION OUTPUT ;
    USE SIGNAL ;
    ANTENNADIFFAREA 0.999200 ;
    PORT
      LAYER Metal3 ;
        RECT 25.540 261.560 40.000 261.760 ;
    END
  END output_o[46]
  PIN output_o[47]
    DIRECTION OUTPUT ;
    USE SIGNAL ;
    ANTENNADIFFAREA 0.662000 ;
    PORT
      LAYER Metal3 ;
        RECT 26.020 266.600 40.000 266.800 ;
    END
  END output_o[47]
  PIN output_o[48]
    DIRECTION OUTPUT ;
    USE SIGNAL ;
    ANTENNADIFFAREA 0.662000 ;
    PORT
      LAYER Metal3 ;
        RECT 33.700 271.640 40.000 271.840 ;
    END
  END output_o[48]
  PIN output_o[49]
    DIRECTION OUTPUT ;
    USE SIGNAL ;
    ANTENNADIFFAREA 0.662000 ;
    PORT
      LAYER Metal3 ;
        RECT 32.260 276.680 40.000 276.880 ;
    END
  END output_o[49]
  PIN output_o[4]
    DIRECTION OUTPUT ;
    USE SIGNAL ;
    ANTENNADIFFAREA 0.662000 ;
    PORT
      LAYER Metal3 ;
        RECT 33.220 49.880 40.000 50.080 ;
    END
  END output_o[4]
  PIN output_o[50]
    DIRECTION OUTPUT ;
    USE SIGNAL ;
    ANTENNADIFFAREA 0.662000 ;
    PORT
      LAYER Metal3 ;
        RECT 35.900 281.720 40.000 281.920 ;
    END
  END output_o[50]
  PIN output_o[51]
    DIRECTION OUTPUT ;
    USE SIGNAL ;
    ANTENNADIFFAREA 0.662000 ;
    PORT
      LAYER Metal3 ;
        RECT 32.740 286.760 40.000 286.960 ;
    END
  END output_o[51]
  PIN output_o[52]
    DIRECTION OUTPUT ;
    USE SIGNAL ;
    ANTENNADIFFAREA 0.662000 ;
    PORT
      LAYER Metal3 ;
        RECT 32.260 291.800 40.000 292.000 ;
    END
  END output_o[52]
  PIN output_o[53]
    DIRECTION OUTPUT ;
    USE SIGNAL ;
    ANTENNADIFFAREA 0.662000 ;
    PORT
      LAYER Metal3 ;
        RECT 36.100 296.840 40.000 297.040 ;
    END
  END output_o[53]
  PIN output_o[54]
    DIRECTION OUTPUT ;
    USE SIGNAL ;
    ANTENNADIFFAREA 0.662000 ;
    PORT
      LAYER Metal3 ;
        RECT 32.740 301.880 40.000 302.080 ;
    END
  END output_o[54]
  PIN output_o[55]
    DIRECTION OUTPUT ;
    USE SIGNAL ;
    ANTENNADIFFAREA 0.662000 ;
    PORT
      LAYER Metal3 ;
        RECT 32.260 306.920 40.000 307.120 ;
    END
  END output_o[55]
  PIN output_o[56]
    DIRECTION OUTPUT ;
    USE SIGNAL ;
    ANTENNADIFFAREA 0.662000 ;
    PORT
      LAYER Metal3 ;
        RECT 35.900 311.960 40.000 312.160 ;
    END
  END output_o[56]
  PIN output_o[57]
    DIRECTION OUTPUT ;
    USE SIGNAL ;
    ANTENNADIFFAREA 0.662000 ;
    PORT
      LAYER Metal3 ;
        RECT 35.140 317.000 40.000 317.200 ;
    END
  END output_o[57]
  PIN output_o[58]
    DIRECTION OUTPUT ;
    USE SIGNAL ;
    ANTENNADIFFAREA 0.662000 ;
    PORT
      LAYER Metal3 ;
        RECT 36.100 322.040 40.000 322.240 ;
    END
  END output_o[58]
  PIN output_o[59]
    DIRECTION OUTPUT ;
    USE SIGNAL ;
    ANTENNADIFFAREA 0.662000 ;
    PORT
      LAYER Metal3 ;
        RECT 34.940 327.080 40.000 327.280 ;
    END
  END output_o[59]
  PIN output_o[5]
    DIRECTION OUTPUT ;
    USE SIGNAL ;
    ANTENNADIFFAREA 0.662000 ;
    PORT
      LAYER Metal3 ;
        RECT 11.620 54.920 40.000 55.120 ;
    END
  END output_o[5]
  PIN output_o[60]
    DIRECTION OUTPUT ;
    USE SIGNAL ;
    ANTENNADIFFAREA 0.662000 ;
    PORT
      LAYER Metal3 ;
        RECT 34.660 332.120 40.000 332.320 ;
    END
  END output_o[60]
  PIN output_o[61]
    DIRECTION OUTPUT ;
    USE SIGNAL ;
    ANTENNADIFFAREA 0.662000 ;
    PORT
      LAYER Metal3 ;
        RECT 36.100 337.160 40.000 337.360 ;
    END
  END output_o[61]
  PIN output_o[62]
    DIRECTION OUTPUT ;
    USE SIGNAL ;
    ANTENNADIFFAREA 0.662000 ;
    PORT
      LAYER Metal3 ;
        RECT 32.060 342.200 40.000 342.400 ;
    END
  END output_o[62]
  PIN output_o[63]
    DIRECTION OUTPUT ;
    USE SIGNAL ;
    ANTENNADIFFAREA 0.662000 ;
    PORT
      LAYER Metal3 ;
        RECT 36.100 347.240 40.000 347.440 ;
    END
  END output_o[63]
  PIN output_o[64]
    DIRECTION OUTPUT ;
    USE SIGNAL ;
    ANTENNADIFFAREA 0.662000 ;
    PORT
      LAYER Metal3 ;
        RECT 32.260 352.280 40.000 352.480 ;
    END
  END output_o[64]
  PIN output_o[65]
    DIRECTION OUTPUT ;
    USE SIGNAL ;
    ANTENNADIFFAREA 0.662000 ;
    PORT
      LAYER Metal3 ;
        RECT 35.620 357.320 40.000 357.520 ;
    END
  END output_o[65]
  PIN output_o[66]
    DIRECTION OUTPUT ;
    USE SIGNAL ;
    ANTENNADIFFAREA 0.662000 ;
    PORT
      LAYER Metal3 ;
        RECT 32.740 362.360 40.000 362.560 ;
    END
  END output_o[66]
  PIN output_o[67]
    DIRECTION OUTPUT ;
    USE SIGNAL ;
    ANTENNADIFFAREA 0.662000 ;
    PORT
      LAYER Metal3 ;
        RECT 34.180 367.400 40.000 367.600 ;
    END
  END output_o[67]
  PIN output_o[68]
    DIRECTION OUTPUT ;
    USE SIGNAL ;
    ANTENNADIFFAREA 0.662000 ;
    PORT
      LAYER Metal3 ;
        RECT 33.980 372.440 40.000 372.640 ;
    END
  END output_o[68]
  PIN output_o[69]
    DIRECTION OUTPUT ;
    USE SIGNAL ;
    ANTENNADIFFAREA 0.662000 ;
    PORT
      LAYER Metal3 ;
        RECT 34.660 377.480 40.000 377.680 ;
    END
  END output_o[69]
  PIN output_o[6]
    DIRECTION OUTPUT ;
    USE SIGNAL ;
    ANTENNADIFFAREA 0.662000 ;
    PORT
      LAYER Metal3 ;
        RECT 10.180 59.960 40.000 60.160 ;
    END
  END output_o[6]
  PIN output_o[70]
    DIRECTION OUTPUT ;
    USE SIGNAL ;
    ANTENNADIFFAREA 0.662000 ;
    PORT
      LAYER Metal3 ;
        RECT 34.180 382.520 40.000 382.720 ;
    END
  END output_o[70]
  PIN output_o[71]
    DIRECTION OUTPUT ;
    USE SIGNAL ;
    ANTENNADIFFAREA 0.662000 ;
    PORT
      LAYER Metal3 ;
        RECT 33.980 387.560 40.000 387.760 ;
    END
  END output_o[71]
  PIN output_o[72]
    DIRECTION OUTPUT ;
    USE SIGNAL ;
    ANTENNADIFFAREA 0.662000 ;
    PORT
      LAYER Metal3 ;
        RECT 34.660 392.600 40.000 392.800 ;
    END
  END output_o[72]
  PIN output_o[73]
    DIRECTION OUTPUT ;
    USE SIGNAL ;
    ANTENNADIFFAREA 0.662000 ;
    PORT
      LAYER Metal3 ;
        RECT 34.180 397.640 40.000 397.840 ;
    END
  END output_o[73]
  PIN output_o[74]
    DIRECTION OUTPUT ;
    USE SIGNAL ;
    ANTENNADIFFAREA 0.662000 ;
    PORT
      LAYER Metal3 ;
        RECT 33.980 402.680 40.000 402.880 ;
    END
  END output_o[74]
  PIN output_o[75]
    DIRECTION OUTPUT ;
    USE SIGNAL ;
    ANTENNADIFFAREA 0.662000 ;
    PORT
      LAYER Metal3 ;
        RECT 34.660 407.720 40.000 407.920 ;
    END
  END output_o[75]
  PIN output_o[76]
    DIRECTION OUTPUT ;
    USE SIGNAL ;
    ANTENNADIFFAREA 0.662000 ;
    PORT
      LAYER Metal3 ;
        RECT 34.180 412.760 40.000 412.960 ;
    END
  END output_o[76]
  PIN output_o[77]
    DIRECTION OUTPUT ;
    USE SIGNAL ;
    ANTENNADIFFAREA 0.662000 ;
    PORT
      LAYER Metal3 ;
        RECT 33.980 417.800 40.000 418.000 ;
    END
  END output_o[77]
  PIN output_o[78]
    DIRECTION OUTPUT ;
    USE SIGNAL ;
    ANTENNADIFFAREA 0.662000 ;
    PORT
      LAYER Metal3 ;
        RECT 34.660 422.840 40.000 423.040 ;
    END
  END output_o[78]
  PIN output_o[79]
    DIRECTION OUTPUT ;
    USE SIGNAL ;
    ANTENNADIFFAREA 0.662000 ;
    PORT
      LAYER Metal3 ;
        RECT 34.180 427.880 40.000 428.080 ;
    END
  END output_o[79]
  PIN output_o[7]
    DIRECTION OUTPUT ;
    USE SIGNAL ;
    ANTENNADIFFAREA 0.662000 ;
    PORT
      LAYER Metal3 ;
        RECT 31.300 65.000 40.000 65.200 ;
    END
  END output_o[7]
  PIN output_o[80]
    DIRECTION OUTPUT ;
    USE SIGNAL ;
    ANTENNADIFFAREA 0.662000 ;
    PORT
      LAYER Metal3 ;
        RECT 33.980 432.920 40.000 433.120 ;
    END
  END output_o[80]
  PIN output_o[81]
    DIRECTION OUTPUT ;
    USE SIGNAL ;
    ANTENNADIFFAREA 0.662000 ;
    PORT
      LAYER Metal3 ;
        RECT 34.660 437.960 40.000 438.160 ;
    END
  END output_o[81]
  PIN output_o[82]
    DIRECTION OUTPUT ;
    USE SIGNAL ;
    ANTENNADIFFAREA 0.662000 ;
    PORT
      LAYER Metal3 ;
        RECT 34.180 443.000 40.000 443.200 ;
    END
  END output_o[82]
  PIN output_o[83]
    DIRECTION OUTPUT ;
    USE SIGNAL ;
    ANTENNADIFFAREA 0.662000 ;
    PORT
      LAYER Metal3 ;
        RECT 33.980 448.040 40.000 448.240 ;
    END
  END output_o[83]
  PIN output_o[84]
    DIRECTION OUTPUT ;
    USE SIGNAL ;
    ANTENNADIFFAREA 0.662000 ;
    PORT
      LAYER Metal3 ;
        RECT 34.660 453.080 40.000 453.280 ;
    END
  END output_o[84]
  PIN output_o[85]
    DIRECTION OUTPUT ;
    USE SIGNAL ;
    ANTENNADIFFAREA 0.662000 ;
    PORT
      LAYER Metal3 ;
        RECT 34.180 458.120 40.000 458.320 ;
    END
  END output_o[85]
  PIN output_o[86]
    DIRECTION OUTPUT ;
    USE SIGNAL ;
    ANTENNADIFFAREA 0.662000 ;
    PORT
      LAYER Metal3 ;
        RECT 33.980 463.160 40.000 463.360 ;
    END
  END output_o[86]
  PIN output_o[87]
    DIRECTION OUTPUT ;
    USE SIGNAL ;
    ANTENNADIFFAREA 0.662000 ;
    PORT
      LAYER Metal3 ;
        RECT 34.660 468.200 40.000 468.400 ;
    END
  END output_o[87]
  PIN output_o[88]
    DIRECTION OUTPUT ;
    USE SIGNAL ;
    ANTENNADIFFAREA 0.662000 ;
    PORT
      LAYER Metal3 ;
        RECT 34.180 473.240 40.000 473.440 ;
    END
  END output_o[88]
  PIN output_o[89]
    DIRECTION OUTPUT ;
    USE SIGNAL ;
    ANTENNADIFFAREA 0.662000 ;
    PORT
      LAYER Metal3 ;
        RECT 33.980 478.280 40.000 478.480 ;
    END
  END output_o[89]
  PIN output_o[8]
    DIRECTION OUTPUT ;
    USE SIGNAL ;
    ANTENNADIFFAREA 0.662000 ;
    PORT
      LAYER Metal3 ;
        RECT 37.540 70.040 40.000 70.240 ;
    END
  END output_o[8]
  PIN output_o[90]
    DIRECTION OUTPUT ;
    USE SIGNAL ;
    ANTENNADIFFAREA 0.662000 ;
    PORT
      LAYER Metal3 ;
        RECT 34.660 483.320 40.000 483.520 ;
    END
  END output_o[90]
  PIN output_o[91]
    DIRECTION OUTPUT ;
    USE SIGNAL ;
    ANTENNADIFFAREA 0.662000 ;
    PORT
      LAYER Metal3 ;
        RECT 34.180 488.360 40.000 488.560 ;
    END
  END output_o[91]
  PIN output_o[92]
    DIRECTION OUTPUT ;
    USE SIGNAL ;
    ANTENNADIFFAREA 0.662000 ;
    PORT
      LAYER Metal3 ;
        RECT 33.980 493.400 40.000 493.600 ;
    END
  END output_o[92]
  PIN output_o[93]
    DIRECTION OUTPUT ;
    USE SIGNAL ;
    ANTENNADIFFAREA 0.662000 ;
    PORT
      LAYER Metal3 ;
        RECT 34.660 498.440 40.000 498.640 ;
    END
  END output_o[93]
  PIN output_o[94]
    DIRECTION OUTPUT ;
    USE SIGNAL ;
    ANTENNADIFFAREA 0.662000 ;
    PORT
      LAYER Metal3 ;
        RECT 34.180 503.480 40.000 503.680 ;
    END
  END output_o[94]
  PIN output_o[95]
    DIRECTION OUTPUT ;
    USE SIGNAL ;
    ANTENNADIFFAREA 0.662000 ;
    PORT
      LAYER Metal3 ;
        RECT 36.580 508.520 40.000 508.720 ;
    END
  END output_o[95]
  PIN output_o[96]
    DIRECTION OUTPUT ;
    USE SIGNAL ;
    ANTENNADIFFAREA 0.662000 ;
    PORT
      LAYER Metal3 ;
        RECT 34.660 513.560 40.000 513.760 ;
    END
  END output_o[96]
  PIN output_o[97]
    DIRECTION OUTPUT ;
    USE SIGNAL ;
    ANTENNADIFFAREA 0.662000 ;
    PORT
      LAYER Metal3 ;
        RECT 34.180 518.600 40.000 518.800 ;
    END
  END output_o[97]
  PIN output_o[98]
    DIRECTION OUTPUT ;
    USE SIGNAL ;
    ANTENNADIFFAREA 0.662000 ;
    PORT
      LAYER Metal3 ;
        RECT 33.980 523.640 40.000 523.840 ;
    END
  END output_o[98]
  PIN output_o[99]
    DIRECTION OUTPUT ;
    USE SIGNAL ;
    ANTENNADIFFAREA 0.662000 ;
    PORT
      LAYER Metal3 ;
        RECT 34.660 528.680 40.000 528.880 ;
    END
  END output_o[99]
  PIN output_o[9]
    DIRECTION OUTPUT ;
    USE SIGNAL ;
    ANTENNADIFFAREA 0.662000 ;
    PORT
      LAYER Metal3 ;
        RECT 12.580 75.080 40.000 75.280 ;
    END
  END output_o[9]
  OBS
      LAYER GatPoly ;
        RECT 2.880 3.630 36.960 695.670 ;
      LAYER Metal1 ;
        RECT 2.880 3.560 36.960 695.740 ;
      LAYER Metal2 ;
        RECT 0.375 3.635 39.945 695.665 ;
      LAYER Metal3 ;
        RECT 0.335 670.630 39.985 695.620 ;
        RECT 0.335 670.210 33.010 670.630 ;
        RECT 0.335 669.590 32.530 670.210 ;
        RECT 0.335 665.590 39.985 669.590 ;
        RECT 0.335 664.970 31.570 665.590 ;
        RECT 0.335 664.550 34.930 664.970 ;
        RECT 0.335 660.550 39.985 664.550 ;
        RECT 0.335 659.930 38.290 660.550 ;
        RECT 0.335 659.510 38.770 659.930 ;
        RECT 0.335 655.930 39.985 659.510 ;
        RECT 9.710 655.510 39.985 655.930 ;
        RECT 9.710 655.310 30.610 655.510 ;
        RECT 0.335 654.890 30.610 655.310 ;
        RECT 0.335 654.470 33.490 654.890 ;
        RECT 0.335 650.470 39.985 654.470 ;
        RECT 0.335 650.050 32.050 650.470 ;
        RECT 0.335 649.430 31.090 650.050 ;
        RECT 0.335 645.430 39.985 649.430 ;
        RECT 0.335 645.010 33.970 645.430 ;
        RECT 0.335 644.390 30.130 645.010 ;
        RECT 0.335 640.390 39.985 644.390 ;
        RECT 0.335 639.970 38.770 640.390 ;
        RECT 0.335 639.350 32.530 639.970 ;
        RECT 0.335 635.350 39.985 639.350 ;
        RECT 0.335 634.730 31.570 635.350 ;
        RECT 0.335 634.310 34.450 634.730 ;
        RECT 0.335 630.310 39.985 634.310 ;
        RECT 0.335 629.690 35.210 630.310 ;
        RECT 0.335 629.270 35.890 629.690 ;
        RECT 0.335 625.270 39.985 629.270 ;
        RECT 0.335 624.850 37.330 625.270 ;
        RECT 0.335 624.230 29.650 624.850 ;
        RECT 0.335 620.230 39.985 624.230 ;
        RECT 0.335 619.810 36.850 620.230 ;
        RECT 0.335 619.190 35.890 619.810 ;
        RECT 0.335 615.190 39.985 619.190 ;
        RECT 0.335 614.770 37.330 615.190 ;
        RECT 0.335 614.150 34.450 614.770 ;
        RECT 0.335 610.150 39.985 614.150 ;
        RECT 0.335 609.530 30.130 610.150 ;
        RECT 0.335 609.110 37.810 609.530 ;
        RECT 0.335 605.110 39.985 609.110 ;
        RECT 0.335 604.690 36.850 605.110 ;
        RECT 0.335 604.070 32.530 604.690 ;
        RECT 0.335 600.070 39.985 604.070 ;
        RECT 0.335 599.650 38.570 600.070 ;
        RECT 0.335 599.030 33.770 599.650 ;
        RECT 0.335 595.030 39.985 599.030 ;
        RECT 0.335 594.410 36.170 595.030 ;
        RECT 0.335 593.990 36.650 594.410 ;
        RECT 0.335 589.990 39.985 593.990 ;
        RECT 0.335 589.370 32.050 589.990 ;
        RECT 0.335 588.950 34.450 589.370 ;
        RECT 0.335 584.950 39.985 588.950 ;
        RECT 0.335 584.530 35.890 584.950 ;
        RECT 0.335 583.910 33.010 584.530 ;
        RECT 0.335 579.910 39.985 583.910 ;
        RECT 0.335 579.290 32.050 579.910 ;
        RECT 0.335 578.870 33.970 579.290 ;
        RECT 0.335 574.870 39.985 578.870 ;
        RECT 0.335 574.250 33.970 574.870 ;
        RECT 0.335 573.830 36.370 574.250 ;
        RECT 0.335 569.830 39.985 573.830 ;
        RECT 0.335 569.410 35.890 569.830 ;
        RECT 0.335 568.790 31.850 569.410 ;
        RECT 0.335 568.570 39.985 568.790 ;
        RECT 28.910 567.950 39.985 568.570 ;
        RECT 0.335 564.790 39.985 567.950 ;
        RECT 0.335 564.170 32.050 564.790 ;
        RECT 0.335 563.750 33.970 564.170 ;
        RECT 0.335 559.750 39.985 563.750 ;
        RECT 0.335 559.130 33.970 559.750 ;
        RECT 0.335 558.710 36.370 559.130 ;
        RECT 0.335 554.710 39.985 558.710 ;
        RECT 0.335 554.290 35.890 554.710 ;
        RECT 0.335 553.670 31.850 554.290 ;
        RECT 0.335 549.670 39.985 553.670 ;
        RECT 0.335 549.050 32.050 549.670 ;
        RECT 0.335 548.630 33.970 549.050 ;
        RECT 0.335 544.630 39.985 548.630 ;
        RECT 0.335 544.010 32.050 544.630 ;
        RECT 0.335 543.590 34.450 544.010 ;
        RECT 0.335 539.590 39.985 543.590 ;
        RECT 0.335 539.170 34.250 539.590 ;
        RECT 0.335 538.550 33.770 539.170 ;
        RECT 0.335 534.550 39.985 538.550 ;
        RECT 0.335 534.130 35.890 534.550 ;
        RECT 0.335 533.510 33.970 534.130 ;
        RECT 0.335 529.510 39.985 533.510 ;
        RECT 0.335 528.890 32.050 529.510 ;
        RECT 0.335 528.470 34.450 528.890 ;
        RECT 0.335 524.470 39.985 528.470 ;
        RECT 0.335 524.050 34.250 524.470 ;
        RECT 0.335 523.430 33.770 524.050 ;
        RECT 0.335 519.430 39.985 523.430 ;
        RECT 0.335 518.810 32.050 519.430 ;
        RECT 0.335 518.390 33.970 518.810 ;
        RECT 0.335 514.390 39.985 518.390 ;
        RECT 0.335 513.770 33.970 514.390 ;
        RECT 0.335 513.350 34.450 513.770 ;
        RECT 0.335 509.350 39.985 513.350 ;
        RECT 0.335 508.730 33.010 509.350 ;
        RECT 0.335 508.310 36.370 508.730 ;
        RECT 0.335 504.310 39.985 508.310 ;
        RECT 0.335 503.690 32.050 504.310 ;
        RECT 0.335 503.270 33.970 503.690 ;
        RECT 0.335 499.270 39.985 503.270 ;
        RECT 0.335 498.650 32.050 499.270 ;
        RECT 0.335 498.230 34.450 498.650 ;
        RECT 0.335 494.230 39.985 498.230 ;
        RECT 0.335 493.810 34.250 494.230 ;
        RECT 0.335 493.190 33.770 493.810 ;
        RECT 0.335 489.190 39.985 493.190 ;
        RECT 0.335 488.570 32.050 489.190 ;
        RECT 0.335 488.150 33.970 488.570 ;
        RECT 0.335 484.150 39.985 488.150 ;
        RECT 0.335 483.530 32.050 484.150 ;
        RECT 0.335 483.110 34.450 483.530 ;
        RECT 0.335 481.210 39.985 483.110 ;
        RECT 29.870 480.590 39.985 481.210 ;
        RECT 0.335 479.110 39.985 480.590 ;
        RECT 0.335 478.690 34.250 479.110 ;
        RECT 0.335 478.070 33.770 478.690 ;
        RECT 0.335 474.070 39.985 478.070 ;
        RECT 0.335 473.450 32.050 474.070 ;
        RECT 0.335 473.030 33.970 473.450 ;
        RECT 0.335 469.030 39.985 473.030 ;
        RECT 0.335 468.610 38.570 469.030 ;
        RECT 0.335 467.990 34.450 468.610 ;
        RECT 0.335 463.990 39.985 467.990 ;
        RECT 0.335 463.570 34.250 463.990 ;
        RECT 0.335 462.950 33.770 463.570 ;
        RECT 0.335 458.950 39.985 462.950 ;
        RECT 0.335 458.330 32.050 458.950 ;
        RECT 0.335 457.910 33.970 458.330 ;
        RECT 0.335 453.910 39.985 457.910 ;
        RECT 0.335 453.290 33.770 453.910 ;
        RECT 0.335 452.870 34.450 453.290 ;
        RECT 0.335 448.870 39.985 452.870 ;
        RECT 0.335 448.450 34.250 448.870 ;
        RECT 0.335 447.830 33.770 448.450 ;
        RECT 0.335 443.830 39.985 447.830 ;
        RECT 0.335 443.210 32.050 443.830 ;
        RECT 0.335 442.790 33.970 443.210 ;
        RECT 0.335 438.790 39.985 442.790 ;
        RECT 0.335 438.170 32.050 438.790 ;
        RECT 0.335 437.750 34.450 438.170 ;
        RECT 0.335 433.750 39.985 437.750 ;
        RECT 0.335 433.330 35.890 433.750 ;
        RECT 0.335 432.710 33.770 433.330 ;
        RECT 0.335 428.710 39.985 432.710 ;
        RECT 0.335 428.090 32.050 428.710 ;
        RECT 0.335 427.670 33.970 428.090 ;
        RECT 0.335 423.670 39.985 427.670 ;
        RECT 0.335 423.050 32.050 423.670 ;
        RECT 0.335 422.630 34.450 423.050 ;
        RECT 0.335 418.630 39.985 422.630 ;
        RECT 0.335 418.210 34.250 418.630 ;
        RECT 0.335 417.590 33.770 418.210 ;
        RECT 0.335 413.590 39.985 417.590 ;
        RECT 0.335 412.970 32.050 413.590 ;
        RECT 0.335 412.550 33.970 412.970 ;
        RECT 0.335 408.550 39.985 412.550 ;
        RECT 0.335 407.930 33.970 408.550 ;
        RECT 0.335 407.510 34.450 407.930 ;
        RECT 0.335 403.510 39.985 407.510 ;
        RECT 0.335 402.890 32.050 403.510 ;
        RECT 0.335 402.470 33.770 402.890 ;
        RECT 0.335 398.470 39.985 402.470 ;
        RECT 0.335 397.850 32.050 398.470 ;
        RECT 0.335 397.430 33.970 397.850 ;
        RECT 0.335 393.850 39.985 397.430 ;
        RECT 1.270 393.430 39.985 393.850 ;
        RECT 1.270 393.230 32.050 393.430 ;
        RECT 0.335 392.810 32.050 393.230 ;
        RECT 0.335 392.390 34.450 392.810 ;
        RECT 0.335 388.390 39.985 392.390 ;
        RECT 0.335 387.970 34.250 388.390 ;
        RECT 0.335 387.350 33.770 387.970 ;
        RECT 0.335 383.350 39.985 387.350 ;
        RECT 0.335 382.730 32.050 383.350 ;
        RECT 0.335 382.310 33.970 382.730 ;
        RECT 0.335 378.310 39.985 382.310 ;
        RECT 0.335 377.690 32.050 378.310 ;
        RECT 0.335 377.270 34.450 377.690 ;
        RECT 0.335 373.270 39.985 377.270 ;
        RECT 0.335 372.650 32.050 373.270 ;
        RECT 0.335 372.230 33.770 372.650 ;
        RECT 0.335 368.230 39.985 372.230 ;
        RECT 0.335 367.610 32.050 368.230 ;
        RECT 0.335 367.190 33.970 367.610 ;
        RECT 0.335 363.190 39.985 367.190 ;
        RECT 0.335 362.770 33.970 363.190 ;
        RECT 0.335 362.150 32.530 362.770 ;
        RECT 0.335 358.150 39.985 362.150 ;
        RECT 0.335 357.530 33.770 358.150 ;
        RECT 0.335 357.110 35.410 357.530 ;
        RECT 0.335 353.110 39.985 357.110 ;
        RECT 0.335 352.690 33.970 353.110 ;
        RECT 0.335 352.070 32.050 352.690 ;
        RECT 0.335 348.070 39.985 352.070 ;
        RECT 0.335 347.450 33.970 348.070 ;
        RECT 0.335 347.030 35.890 347.450 ;
        RECT 0.335 343.030 39.985 347.030 ;
        RECT 0.335 342.610 33.970 343.030 ;
        RECT 0.335 341.990 31.850 342.610 ;
        RECT 0.335 337.990 39.985 341.990 ;
        RECT 0.335 337.370 33.970 337.990 ;
        RECT 0.335 336.950 35.890 337.370 ;
        RECT 0.335 332.950 39.985 336.950 ;
        RECT 0.335 332.330 33.970 332.950 ;
        RECT 0.335 331.910 34.450 332.330 ;
        RECT 0.335 327.910 39.985 331.910 ;
        RECT 0.335 327.490 35.410 327.910 ;
        RECT 0.335 326.870 34.730 327.490 ;
        RECT 0.335 322.870 39.985 326.870 ;
        RECT 0.335 322.250 34.450 322.870 ;
        RECT 0.335 321.830 35.890 322.250 ;
        RECT 0.335 317.830 39.985 321.830 ;
        RECT 0.335 317.210 32.050 317.830 ;
        RECT 0.335 316.790 34.930 317.210 ;
        RECT 0.335 312.790 39.985 316.790 ;
        RECT 0.335 312.370 36.170 312.790 ;
        RECT 0.335 311.750 35.690 312.370 ;
        RECT 0.335 307.750 39.985 311.750 ;
        RECT 0.335 307.330 33.970 307.750 ;
        RECT 0.335 306.710 32.050 307.330 ;
        RECT 0.335 306.490 39.985 306.710 ;
        RECT 12.790 305.870 39.985 306.490 ;
        RECT 0.335 302.710 39.985 305.870 ;
        RECT 0.335 302.290 33.970 302.710 ;
        RECT 0.335 301.670 32.530 302.290 ;
        RECT 0.335 297.670 39.985 301.670 ;
        RECT 0.335 297.050 33.970 297.670 ;
        RECT 0.335 296.630 35.890 297.050 ;
        RECT 0.335 292.630 39.985 296.630 ;
        RECT 0.335 292.210 33.970 292.630 ;
        RECT 0.335 291.590 32.050 292.210 ;
        RECT 0.335 287.590 39.985 291.590 ;
        RECT 0.335 287.170 33.970 287.590 ;
        RECT 0.335 286.550 32.530 287.170 ;
        RECT 0.335 282.550 39.985 286.550 ;
        RECT 0.335 281.930 33.970 282.550 ;
        RECT 0.335 281.510 35.690 281.930 ;
        RECT 0.335 277.510 39.985 281.510 ;
        RECT 0.335 277.090 33.970 277.510 ;
        RECT 0.335 276.470 32.050 277.090 ;
        RECT 0.335 272.470 39.985 276.470 ;
        RECT 0.335 272.050 35.890 272.470 ;
        RECT 0.335 271.430 33.490 272.050 ;
        RECT 0.335 267.430 39.985 271.430 ;
        RECT 0.335 267.010 32.050 267.430 ;
        RECT 0.335 266.390 25.810 267.010 ;
        RECT 0.335 262.390 39.985 266.390 ;
        RECT 0.335 261.970 35.410 262.390 ;
        RECT 0.335 261.350 25.330 261.970 ;
        RECT 0.335 257.350 39.985 261.350 ;
        RECT 0.335 256.930 33.970 257.350 ;
        RECT 0.335 256.310 24.370 256.930 ;
        RECT 0.335 252.310 39.985 256.310 ;
        RECT 0.335 251.890 37.130 252.310 ;
        RECT 0.335 251.270 34.450 251.890 ;
        RECT 0.335 247.270 39.985 251.270 ;
        RECT 0.335 246.650 28.490 247.270 ;
        RECT 0.335 246.230 28.970 246.650 ;
        RECT 0.335 242.230 39.985 246.230 ;
        RECT 0.335 241.810 34.450 242.230 ;
        RECT 0.335 241.190 24.370 241.810 ;
        RECT 0.335 237.190 39.985 241.190 ;
        RECT 0.335 236.770 33.490 237.190 ;
        RECT 0.335 236.150 23.890 236.770 ;
        RECT 0.335 232.150 39.985 236.150 ;
        RECT 0.335 231.530 33.970 232.150 ;
        RECT 0.335 231.110 34.450 231.530 ;
        RECT 0.335 227.110 39.985 231.110 ;
        RECT 0.335 226.690 29.650 227.110 ;
        RECT 0.335 226.070 23.410 226.690 ;
        RECT 0.335 222.070 39.985 226.070 ;
        RECT 0.335 221.650 33.770 222.070 ;
        RECT 0.335 221.030 22.930 221.650 ;
        RECT 0.335 219.130 39.985 221.030 ;
        RECT 18.830 218.510 39.985 219.130 ;
        RECT 0.335 217.030 39.985 218.510 ;
        RECT 0.335 216.410 33.770 217.030 ;
        RECT 0.335 215.990 34.250 216.410 ;
        RECT 0.335 211.990 39.985 215.990 ;
        RECT 0.335 211.570 34.450 211.990 ;
        RECT 0.335 210.950 33.010 211.570 ;
        RECT 0.335 206.950 39.985 210.950 ;
        RECT 0.335 206.530 33.970 206.950 ;
        RECT 0.335 205.910 30.410 206.530 ;
        RECT 0.335 201.910 39.985 205.910 ;
        RECT 0.335 201.490 32.050 201.910 ;
        RECT 0.335 200.870 28.690 201.490 ;
        RECT 0.335 196.870 39.985 200.870 ;
        RECT 0.335 196.450 35.410 196.870 ;
        RECT 0.335 195.830 33.970 196.450 ;
        RECT 0.335 191.830 39.985 195.830 ;
        RECT 0.335 191.410 32.050 191.830 ;
        RECT 0.335 190.790 24.170 191.410 ;
        RECT 0.335 186.790 39.985 190.790 ;
        RECT 0.335 186.170 33.970 186.790 ;
        RECT 0.335 185.750 35.690 186.170 ;
        RECT 0.335 181.750 39.985 185.750 ;
        RECT 0.335 181.330 34.450 181.750 ;
        RECT 0.335 180.710 21.490 181.330 ;
        RECT 0.335 176.710 39.985 180.710 ;
        RECT 0.335 176.290 34.450 176.710 ;
        RECT 0.335 175.670 21.010 176.290 ;
        RECT 0.335 171.670 39.985 175.670 ;
        RECT 0.335 171.250 35.890 171.670 ;
        RECT 0.335 170.630 34.450 171.250 ;
        RECT 0.335 166.630 39.985 170.630 ;
        RECT 0.335 166.210 28.210 166.630 ;
        RECT 0.335 165.590 22.450 166.210 ;
        RECT 0.335 161.590 39.985 165.590 ;
        RECT 0.335 161.170 27.530 161.590 ;
        RECT 0.335 160.550 21.490 161.170 ;
        RECT 0.335 156.550 39.985 160.550 ;
        RECT 0.335 156.130 33.770 156.550 ;
        RECT 0.335 155.510 21.490 156.130 ;
        RECT 0.335 151.510 39.985 155.510 ;
        RECT 0.335 151.090 35.890 151.510 ;
        RECT 0.335 150.470 34.450 151.090 ;
        RECT 0.335 146.470 39.985 150.470 ;
        RECT 0.335 146.050 24.650 146.470 ;
        RECT 0.335 145.430 21.490 146.050 ;
        RECT 0.335 141.430 39.985 145.430 ;
        RECT 0.335 140.810 34.250 141.430 ;
        RECT 0.335 140.390 38.570 140.810 ;
        RECT 0.335 136.390 39.985 140.390 ;
        RECT 0.335 135.970 34.450 136.390 ;
        RECT 0.335 135.350 22.450 135.970 ;
        RECT 0.335 131.770 39.985 135.350 ;
        RECT 17.870 131.350 39.985 131.770 ;
        RECT 17.870 131.150 35.890 131.350 ;
        RECT 0.335 130.930 35.890 131.150 ;
        RECT 0.335 130.310 34.250 130.930 ;
        RECT 0.335 126.310 39.985 130.310 ;
        RECT 0.335 125.890 35.890 126.310 ;
        RECT 0.335 125.270 34.450 125.890 ;
        RECT 0.335 121.270 39.985 125.270 ;
        RECT 0.335 120.850 35.890 121.270 ;
        RECT 0.335 120.230 34.450 120.850 ;
        RECT 0.335 116.230 39.985 120.230 ;
        RECT 0.335 115.810 35.890 116.230 ;
        RECT 0.335 115.190 34.450 115.810 ;
        RECT 0.335 111.190 39.985 115.190 ;
        RECT 0.335 110.770 31.850 111.190 ;
        RECT 0.335 110.150 27.250 110.770 ;
        RECT 0.335 106.150 39.985 110.150 ;
        RECT 0.335 105.730 17.450 106.150 ;
        RECT 0.335 105.110 11.890 105.730 ;
        RECT 0.335 101.110 39.985 105.110 ;
        RECT 0.335 100.690 36.850 101.110 ;
        RECT 0.335 100.070 10.450 100.690 ;
        RECT 0.335 96.070 39.985 100.070 ;
        RECT 0.335 95.650 34.930 96.070 ;
        RECT 0.335 95.030 10.930 95.650 ;
        RECT 0.335 91.030 39.985 95.030 ;
        RECT 0.335 90.610 38.570 91.030 ;
        RECT 0.335 89.990 33.970 90.610 ;
        RECT 0.335 85.990 39.985 89.990 ;
        RECT 0.335 85.570 30.610 85.990 ;
        RECT 0.335 84.950 9.490 85.570 ;
        RECT 0.335 80.950 39.985 84.950 ;
        RECT 0.335 80.530 36.370 80.950 ;
        RECT 0.335 79.910 12.370 80.530 ;
        RECT 0.335 75.910 39.985 79.910 ;
        RECT 0.335 75.490 36.650 75.910 ;
        RECT 0.335 74.870 12.370 75.490 ;
        RECT 0.335 70.870 39.985 74.870 ;
        RECT 0.335 70.450 37.810 70.870 ;
        RECT 0.335 69.830 37.330 70.450 ;
        RECT 0.335 65.830 39.985 69.830 ;
        RECT 0.335 65.210 8.530 65.830 ;
        RECT 0.335 64.790 31.090 65.210 ;
        RECT 0.335 60.790 39.985 64.790 ;
        RECT 0.335 60.370 18.610 60.790 ;
        RECT 0.335 59.750 9.970 60.370 ;
        RECT 0.335 55.750 39.985 59.750 ;
        RECT 0.335 55.330 32.530 55.750 ;
        RECT 0.335 54.710 11.410 55.330 ;
        RECT 0.335 50.710 39.985 54.710 ;
        RECT 0.335 50.290 38.770 50.710 ;
        RECT 0.335 49.670 33.010 50.290 ;
        RECT 0.335 45.670 39.985 49.670 ;
        RECT 0.335 45.250 38.570 45.670 ;
        RECT 0.335 44.630 34.450 45.250 ;
        RECT 0.335 44.410 39.985 44.630 ;
        RECT 29.390 43.790 39.985 44.410 ;
        RECT 0.335 40.630 39.985 43.790 ;
        RECT 0.335 39.590 38.290 40.630 ;
        RECT 0.335 35.590 39.985 39.590 ;
        RECT 0.335 34.970 37.810 35.590 ;
        RECT 0.335 34.550 38.570 34.970 ;
        RECT 0.335 30.550 39.985 34.550 ;
        RECT 0.335 29.930 30.130 30.550 ;
        RECT 0.335 29.510 38.770 29.930 ;
        RECT 0.335 3.680 39.985 29.510 ;
      LAYER Metal4 ;
        RECT 12.380 3.635 39.940 695.665 ;
      LAYER Metal5 ;
        RECT 13.775 3.470 39.025 695.830 ;
      LAYER TopMetal1 ;
        RECT 30.460 94.940 32.100 252.820 ;
  END
END vdecoder
END LIBRARY

